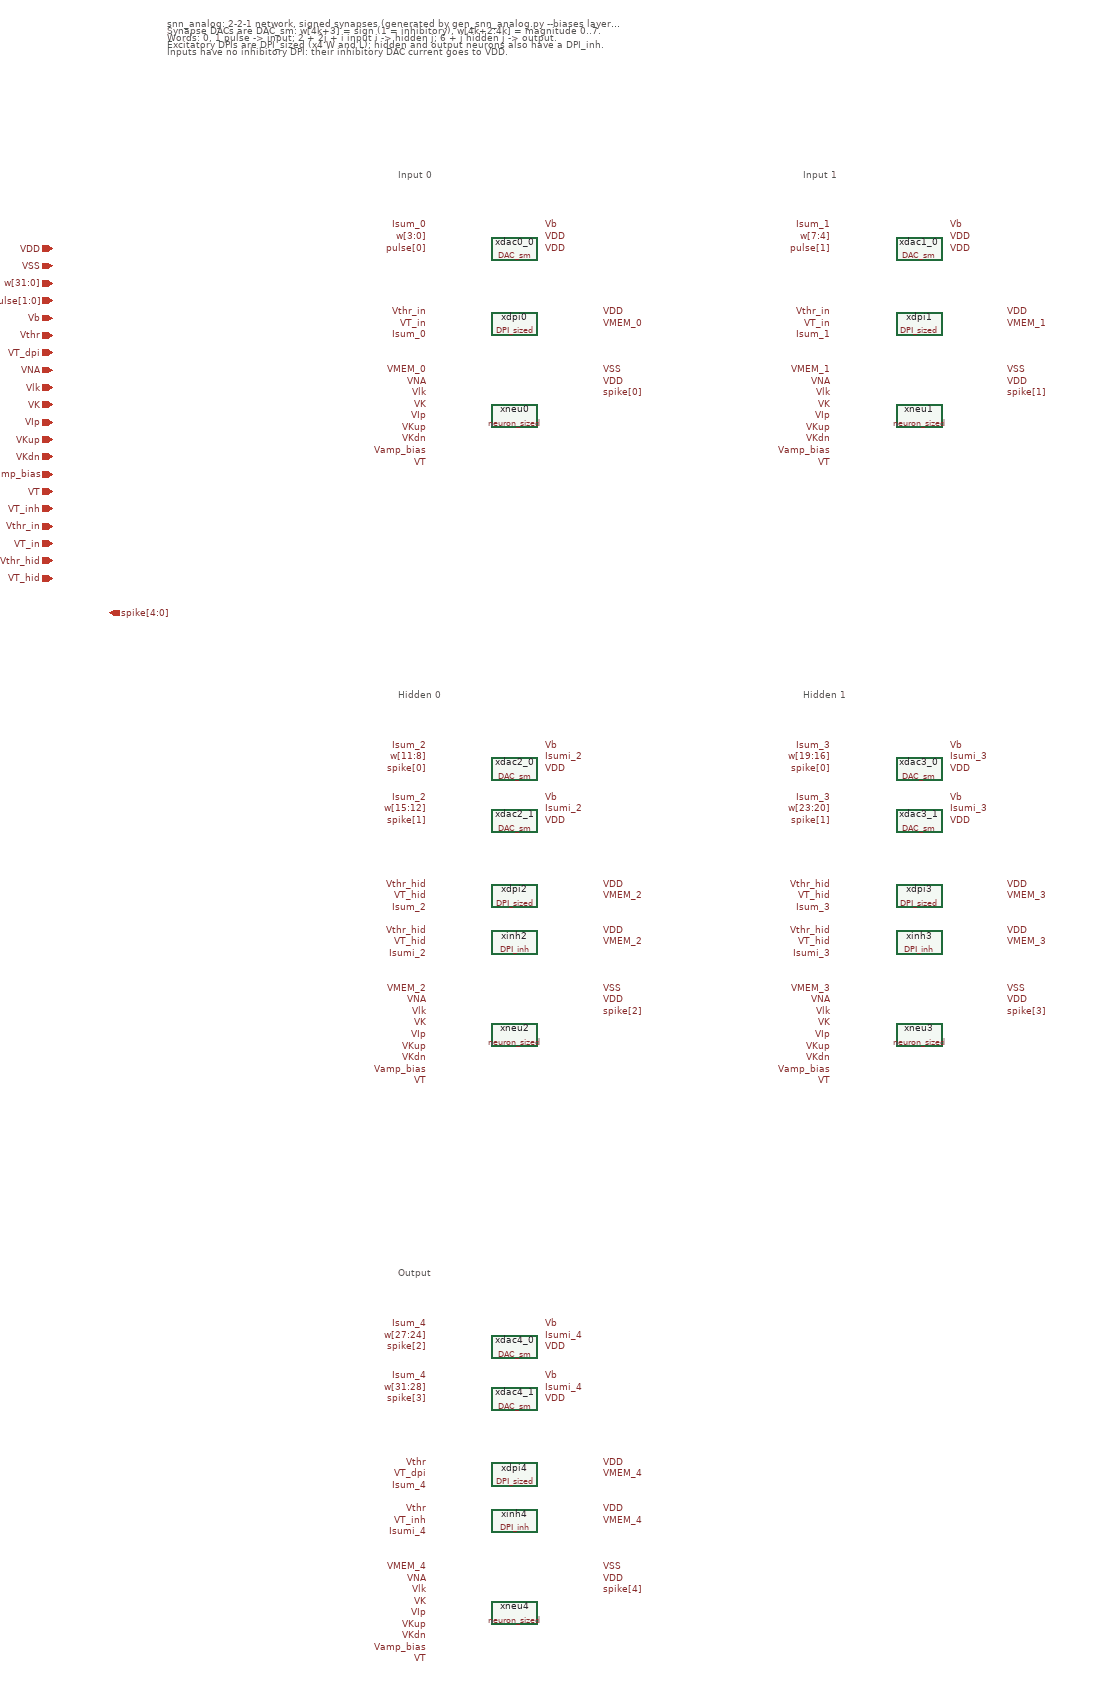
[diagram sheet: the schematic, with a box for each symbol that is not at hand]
v {xschem version=3.4.8RC file_version=1.3}
G {}
K {}
V {}
S {}
F {}
E {}
T {snn_analog: 2-2-1 network, signed synapses (generated by gen_snn_analog.py --biases layer).
Synapse DACs are DAC_sm: w[4k+3] = sign (1 = inhibitory), w[4k+2:4k] = magnitude 0..7.
Words: 0, 1 pulse -> input; 2 + 2j + i input i -> hidden j; 6 + j hidden j -> output.
Excitatory DPIs are DPI_sized (x4 W and L); hidden and output neurons also have a DPI_inh.
Inputs have no inhibitory DPI: their inhibitory DAC current goes to VDD.} -200 -1700 0 0 0.3 0.3 {}
T {Input 0} 200 -1440 0 0 0.4 0.4 {}
C {DAC_sm.sym} 400 -1300 0 0 {name=xdac0_0}
C {lab_pin.sym} 250 -1340 0 0 {name=l1 sig_type=std_logic lab=Isum_0}
C {lab_pin.sym} 250 -1320 0 0 {name=l2 sig_type=std_logic lab=w[3:0]}
C {lab_pin.sym} 250 -1300 0 0 {name=l3 sig_type=std_logic lab=pulse[0]}
C {lab_pin.sym} 450 -1340 0 1 {name=l4 sig_type=std_logic lab=Vb}
C {lab_pin.sym} 450 -1320 0 1 {name=l5 sig_type=std_logic lab=VDD}
C {lab_pin.sym} 450 -1300 0 1 {name=l6 sig_type=std_logic lab=VDD}
C {DPI_sized.sym} 400 -1170 0 0 {name=xdpi0}
C {lab_pin.sym} 550 -1190 0 1 {name=l7 sig_type=std_logic lab=VDD}
C {lab_pin.sym} 250 -1190 0 0 {name=l8 sig_type=std_logic lab=Vthr_in}
C {lab_pin.sym} 550 -1170 0 1 {name=l9 sig_type=std_logic lab=VMEM_0}
C {lab_pin.sym} 250 -1150 0 0 {name=l10 sig_type=std_logic lab=Isum_0}
C {lab_pin.sym} 250 -1170 0 0 {name=l11 sig_type=std_logic lab=VT_in}
C {neuron_sized.sym} 400 -1010 0 0 {name=xneu0}
C {lab_pin.sym} 550 -1090 0 1 {name=l12 sig_type=std_logic lab=VSS}
C {lab_pin.sym} 550 -1070 0 1 {name=l13 sig_type=std_logic lab=VDD}
C {lab_pin.sym} 250 -1090 0 0 {name=l14 sig_type=std_logic lab=VMEM_0}
C {lab_pin.sym} 550 -1050 0 1 {name=l15 sig_type=std_logic lab=spike[0]}
C {lab_pin.sym} 250 -1070 0 0 {name=l16 sig_type=std_logic lab=VNA}
C {lab_pin.sym} 250 -1050 0 0 {name=l17 sig_type=std_logic lab=Vlk}
C {lab_pin.sym} 250 -1030 0 0 {name=l18 sig_type=std_logic lab=VK}
C {lab_pin.sym} 250 -1010 0 0 {name=l19 sig_type=std_logic lab=VIp}
C {lab_pin.sym} 250 -990 0 0 {name=l20 sig_type=std_logic lab=VKup}
C {lab_pin.sym} 250 -970 0 0 {name=l21 sig_type=std_logic lab=VKdn}
C {lab_pin.sym} 250 -950 0 0 {name=l22 sig_type=std_logic lab=Vamp_bias}
C {lab_pin.sym} 250 -930 0 0 {name=l23 sig_type=std_logic lab=VT}
T {Input 1} 900 -1440 0 0 0.4 0.4 {}
C {DAC_sm.sym} 1100 -1300 0 0 {name=xdac1_0}
C {lab_pin.sym} 950 -1340 0 0 {name=l24 sig_type=std_logic lab=Isum_1}
C {lab_pin.sym} 950 -1320 0 0 {name=l25 sig_type=std_logic lab=w[7:4]}
C {lab_pin.sym} 950 -1300 0 0 {name=l26 sig_type=std_logic lab=pulse[1]}
C {lab_pin.sym} 1150 -1340 0 1 {name=l27 sig_type=std_logic lab=Vb}
C {lab_pin.sym} 1150 -1320 0 1 {name=l28 sig_type=std_logic lab=VDD}
C {lab_pin.sym} 1150 -1300 0 1 {name=l29 sig_type=std_logic lab=VDD}
C {DPI_sized.sym} 1100 -1170 0 0 {name=xdpi1}
C {lab_pin.sym} 1250 -1190 0 1 {name=l30 sig_type=std_logic lab=VDD}
C {lab_pin.sym} 950 -1190 0 0 {name=l31 sig_type=std_logic lab=Vthr_in}
C {lab_pin.sym} 1250 -1170 0 1 {name=l32 sig_type=std_logic lab=VMEM_1}
C {lab_pin.sym} 950 -1150 0 0 {name=l33 sig_type=std_logic lab=Isum_1}
C {lab_pin.sym} 950 -1170 0 0 {name=l34 sig_type=std_logic lab=VT_in}
C {neuron_sized.sym} 1100 -1010 0 0 {name=xneu1}
C {lab_pin.sym} 1250 -1090 0 1 {name=l35 sig_type=std_logic lab=VSS}
C {lab_pin.sym} 1250 -1070 0 1 {name=l36 sig_type=std_logic lab=VDD}
C {lab_pin.sym} 950 -1090 0 0 {name=l37 sig_type=std_logic lab=VMEM_1}
C {lab_pin.sym} 1250 -1050 0 1 {name=l38 sig_type=std_logic lab=spike[1]}
C {lab_pin.sym} 950 -1070 0 0 {name=l39 sig_type=std_logic lab=VNA}
C {lab_pin.sym} 950 -1050 0 0 {name=l40 sig_type=std_logic lab=Vlk}
C {lab_pin.sym} 950 -1030 0 0 {name=l41 sig_type=std_logic lab=VK}
C {lab_pin.sym} 950 -1010 0 0 {name=l42 sig_type=std_logic lab=VIp}
C {lab_pin.sym} 950 -990 0 0 {name=l43 sig_type=std_logic lab=VKup}
C {lab_pin.sym} 950 -970 0 0 {name=l44 sig_type=std_logic lab=VKdn}
C {lab_pin.sym} 950 -950 0 0 {name=l45 sig_type=std_logic lab=Vamp_bias}
C {lab_pin.sym} 950 -930 0 0 {name=l46 sig_type=std_logic lab=VT}
T {Hidden 0} 200 -540 0 0 0.4 0.4 {}
C {DAC_sm.sym} 400 -400 0 0 {name=xdac2_0}
C {lab_pin.sym} 250 -440 0 0 {name=l47 sig_type=std_logic lab=Isum_2}
C {lab_pin.sym} 250 -420 0 0 {name=l48 sig_type=std_logic lab=w[11:8]}
C {lab_pin.sym} 250 -400 0 0 {name=l49 sig_type=std_logic lab=spike[0]}
C {lab_pin.sym} 450 -440 0 1 {name=l50 sig_type=std_logic lab=Vb}
C {lab_pin.sym} 450 -420 0 1 {name=l51 sig_type=std_logic lab=Isumi_2}
C {lab_pin.sym} 450 -400 0 1 {name=l52 sig_type=std_logic lab=VDD}
C {DAC_sm.sym} 400 -310 0 0 {name=xdac2_1}
C {lab_pin.sym} 250 -350 0 0 {name=l53 sig_type=std_logic lab=Isum_2}
C {lab_pin.sym} 250 -330 0 0 {name=l54 sig_type=std_logic lab=w[15:12]}
C {lab_pin.sym} 250 -310 0 0 {name=l55 sig_type=std_logic lab=spike[1]}
C {lab_pin.sym} 450 -350 0 1 {name=l56 sig_type=std_logic lab=Vb}
C {lab_pin.sym} 450 -330 0 1 {name=l57 sig_type=std_logic lab=Isumi_2}
C {lab_pin.sym} 450 -310 0 1 {name=l58 sig_type=std_logic lab=VDD}
C {DPI_sized.sym} 400 -180 0 0 {name=xdpi2}
C {lab_pin.sym} 550 -200 0 1 {name=l59 sig_type=std_logic lab=VDD}
C {lab_pin.sym} 250 -200 0 0 {name=l60 sig_type=std_logic lab=Vthr_hid}
C {lab_pin.sym} 550 -180 0 1 {name=l61 sig_type=std_logic lab=VMEM_2}
C {lab_pin.sym} 250 -160 0 0 {name=l62 sig_type=std_logic lab=Isum_2}
C {lab_pin.sym} 250 -180 0 0 {name=l63 sig_type=std_logic lab=VT_hid}
C {DPI_inh.sym} 400 -100 0 0 {name=xinh2}
C {lab_pin.sym} 250 -120 0 0 {name=l64 sig_type=std_logic lab=Vthr_hid}
C {lab_pin.sym} 250 -100 0 0 {name=l65 sig_type=std_logic lab=VT_hid}
C {lab_pin.sym} 250 -80 0 0 {name=l66 sig_type=std_logic lab=Isumi_2}
C {lab_pin.sym} 550 -120 0 1 {name=l67 sig_type=std_logic lab=VDD}
C {lab_pin.sym} 550 -100 0 1 {name=l68 sig_type=std_logic lab=VMEM_2}
C {neuron_sized.sym} 400 60 0 0 {name=xneu2}
C {lab_pin.sym} 550 -20 0 1 {name=l69 sig_type=std_logic lab=VSS}
C {lab_pin.sym} 550 0 0 1 {name=l70 sig_type=std_logic lab=VDD}
C {lab_pin.sym} 250 -20 0 0 {name=l71 sig_type=std_logic lab=VMEM_2}
C {lab_pin.sym} 550 20 0 1 {name=l72 sig_type=std_logic lab=spike[2]}
C {lab_pin.sym} 250 0 0 0 {name=l73 sig_type=std_logic lab=VNA}
C {lab_pin.sym} 250 20 0 0 {name=l74 sig_type=std_logic lab=Vlk}
C {lab_pin.sym} 250 40 0 0 {name=l75 sig_type=std_logic lab=VK}
C {lab_pin.sym} 250 60 0 0 {name=l76 sig_type=std_logic lab=VIp}
C {lab_pin.sym} 250 80 0 0 {name=l77 sig_type=std_logic lab=VKup}
C {lab_pin.sym} 250 100 0 0 {name=l78 sig_type=std_logic lab=VKdn}
C {lab_pin.sym} 250 120 0 0 {name=l79 sig_type=std_logic lab=Vamp_bias}
C {lab_pin.sym} 250 140 0 0 {name=l80 sig_type=std_logic lab=VT}
T {Hidden 1} 900 -540 0 0 0.4 0.4 {}
C {DAC_sm.sym} 1100 -400 0 0 {name=xdac3_0}
C {lab_pin.sym} 950 -440 0 0 {name=l81 sig_type=std_logic lab=Isum_3}
C {lab_pin.sym} 950 -420 0 0 {name=l82 sig_type=std_logic lab=w[19:16]}
C {lab_pin.sym} 950 -400 0 0 {name=l83 sig_type=std_logic lab=spike[0]}
C {lab_pin.sym} 1150 -440 0 1 {name=l84 sig_type=std_logic lab=Vb}
C {lab_pin.sym} 1150 -420 0 1 {name=l85 sig_type=std_logic lab=Isumi_3}
C {lab_pin.sym} 1150 -400 0 1 {name=l86 sig_type=std_logic lab=VDD}
C {DAC_sm.sym} 1100 -310 0 0 {name=xdac3_1}
C {lab_pin.sym} 950 -350 0 0 {name=l87 sig_type=std_logic lab=Isum_3}
C {lab_pin.sym} 950 -330 0 0 {name=l88 sig_type=std_logic lab=w[23:20]}
C {lab_pin.sym} 950 -310 0 0 {name=l89 sig_type=std_logic lab=spike[1]}
C {lab_pin.sym} 1150 -350 0 1 {name=l90 sig_type=std_logic lab=Vb}
C {lab_pin.sym} 1150 -330 0 1 {name=l91 sig_type=std_logic lab=Isumi_3}
C {lab_pin.sym} 1150 -310 0 1 {name=l92 sig_type=std_logic lab=VDD}
C {DPI_sized.sym} 1100 -180 0 0 {name=xdpi3}
C {lab_pin.sym} 1250 -200 0 1 {name=l93 sig_type=std_logic lab=VDD}
C {lab_pin.sym} 950 -200 0 0 {name=l94 sig_type=std_logic lab=Vthr_hid}
C {lab_pin.sym} 1250 -180 0 1 {name=l95 sig_type=std_logic lab=VMEM_3}
C {lab_pin.sym} 950 -160 0 0 {name=l96 sig_type=std_logic lab=Isum_3}
C {lab_pin.sym} 950 -180 0 0 {name=l97 sig_type=std_logic lab=VT_hid}
C {DPI_inh.sym} 1100 -100 0 0 {name=xinh3}
C {lab_pin.sym} 950 -120 0 0 {name=l98 sig_type=std_logic lab=Vthr_hid}
C {lab_pin.sym} 950 -100 0 0 {name=l99 sig_type=std_logic lab=VT_hid}
C {lab_pin.sym} 950 -80 0 0 {name=l100 sig_type=std_logic lab=Isumi_3}
C {lab_pin.sym} 1250 -120 0 1 {name=l101 sig_type=std_logic lab=VDD}
C {lab_pin.sym} 1250 -100 0 1 {name=l102 sig_type=std_logic lab=VMEM_3}
C {neuron_sized.sym} 1100 60 0 0 {name=xneu3}
C {lab_pin.sym} 1250 -20 0 1 {name=l103 sig_type=std_logic lab=VSS}
C {lab_pin.sym} 1250 0 0 1 {name=l104 sig_type=std_logic lab=VDD}
C {lab_pin.sym} 950 -20 0 0 {name=l105 sig_type=std_logic lab=VMEM_3}
C {lab_pin.sym} 1250 20 0 1 {name=l106 sig_type=std_logic lab=spike[3]}
C {lab_pin.sym} 950 0 0 0 {name=l107 sig_type=std_logic lab=VNA}
C {lab_pin.sym} 950 20 0 0 {name=l108 sig_type=std_logic lab=Vlk}
C {lab_pin.sym} 950 40 0 0 {name=l109 sig_type=std_logic lab=VK}
C {lab_pin.sym} 950 60 0 0 {name=l110 sig_type=std_logic lab=VIp}
C {lab_pin.sym} 950 80 0 0 {name=l111 sig_type=std_logic lab=VKup}
C {lab_pin.sym} 950 100 0 0 {name=l112 sig_type=std_logic lab=VKdn}
C {lab_pin.sym} 950 120 0 0 {name=l113 sig_type=std_logic lab=Vamp_bias}
C {lab_pin.sym} 950 140 0 0 {name=l114 sig_type=std_logic lab=VT}
T {Output} 200 460 0 0 0.4 0.4 {}
C {DAC_sm.sym} 400 600 0 0 {name=xdac4_0}
C {lab_pin.sym} 250 560 0 0 {name=l115 sig_type=std_logic lab=Isum_4}
C {lab_pin.sym} 250 580 0 0 {name=l116 sig_type=std_logic lab=w[27:24]}
C {lab_pin.sym} 250 600 0 0 {name=l117 sig_type=std_logic lab=spike[2]}
C {lab_pin.sym} 450 560 0 1 {name=l118 sig_type=std_logic lab=Vb}
C {lab_pin.sym} 450 580 0 1 {name=l119 sig_type=std_logic lab=Isumi_4}
C {lab_pin.sym} 450 600 0 1 {name=l120 sig_type=std_logic lab=VDD}
C {DAC_sm.sym} 400 690 0 0 {name=xdac4_1}
C {lab_pin.sym} 250 650 0 0 {name=l121 sig_type=std_logic lab=Isum_4}
C {lab_pin.sym} 250 670 0 0 {name=l122 sig_type=std_logic lab=w[31:28]}
C {lab_pin.sym} 250 690 0 0 {name=l123 sig_type=std_logic lab=spike[3]}
C {lab_pin.sym} 450 650 0 1 {name=l124 sig_type=std_logic lab=Vb}
C {lab_pin.sym} 450 670 0 1 {name=l125 sig_type=std_logic lab=Isumi_4}
C {lab_pin.sym} 450 690 0 1 {name=l126 sig_type=std_logic lab=VDD}
C {DPI_sized.sym} 400 820 0 0 {name=xdpi4}
C {lab_pin.sym} 550 800 0 1 {name=l127 sig_type=std_logic lab=VDD}
C {lab_pin.sym} 250 800 0 0 {name=l128 sig_type=std_logic lab=Vthr}
C {lab_pin.sym} 550 820 0 1 {name=l129 sig_type=std_logic lab=VMEM_4}
C {lab_pin.sym} 250 840 0 0 {name=l130 sig_type=std_logic lab=Isum_4}
C {lab_pin.sym} 250 820 0 0 {name=l131 sig_type=std_logic lab=VT_dpi}
C {DPI_inh.sym} 400 900 0 0 {name=xinh4}
C {lab_pin.sym} 250 880 0 0 {name=l132 sig_type=std_logic lab=Vthr}
C {lab_pin.sym} 250 900 0 0 {name=l133 sig_type=std_logic lab=VT_inh}
C {lab_pin.sym} 250 920 0 0 {name=l134 sig_type=std_logic lab=Isumi_4}
C {lab_pin.sym} 550 880 0 1 {name=l135 sig_type=std_logic lab=VDD}
C {lab_pin.sym} 550 900 0 1 {name=l136 sig_type=std_logic lab=VMEM_4}
C {neuron_sized.sym} 400 1060 0 0 {name=xneu4}
C {lab_pin.sym} 550 980 0 1 {name=l137 sig_type=std_logic lab=VSS}
C {lab_pin.sym} 550 1000 0 1 {name=l138 sig_type=std_logic lab=VDD}
C {lab_pin.sym} 250 980 0 0 {name=l139 sig_type=std_logic lab=VMEM_4}
C {lab_pin.sym} 550 1020 0 1 {name=l140 sig_type=std_logic lab=spike[4]}
C {lab_pin.sym} 250 1000 0 0 {name=l141 sig_type=std_logic lab=VNA}
C {lab_pin.sym} 250 1020 0 0 {name=l142 sig_type=std_logic lab=Vlk}
C {lab_pin.sym} 250 1040 0 0 {name=l143 sig_type=std_logic lab=VK}
C {lab_pin.sym} 250 1060 0 0 {name=l144 sig_type=std_logic lab=VIp}
C {lab_pin.sym} 250 1080 0 0 {name=l145 sig_type=std_logic lab=VKup}
C {lab_pin.sym} 250 1100 0 0 {name=l146 sig_type=std_logic lab=VKdn}
C {lab_pin.sym} 250 1120 0 0 {name=l147 sig_type=std_logic lab=Vamp_bias}
C {lab_pin.sym} 250 1140 0 0 {name=l148 sig_type=std_logic lab=VT}
C {iopin.sym} -400 -1300 0 0 {name=p0 lab=VDD}
C {iopin.sym} -400 -1270 0 0 {name=p1 lab=VSS}
C {ipin.sym} -400 -1240 0 0 {name=p2 lab=w[31:0]}
C {ipin.sym} -400 -1210 0 0 {name=p3 lab=pulse[1:0]}
C {ipin.sym} -400 -1180 0 0 {name=p4 lab=Vb}
C {ipin.sym} -400 -1150 0 0 {name=p5 lab=Vthr}
C {ipin.sym} -400 -1120 0 0 {name=p6 lab=VT_dpi}
C {ipin.sym} -400 -1090 0 0 {name=p7 lab=VNA}
C {ipin.sym} -400 -1060 0 0 {name=p8 lab=Vlk}
C {ipin.sym} -400 -1030 0 0 {name=p9 lab=VK}
C {ipin.sym} -400 -1000 0 0 {name=p10 lab=VIp}
C {ipin.sym} -400 -970 0 0 {name=p11 lab=VKup}
C {ipin.sym} -400 -940 0 0 {name=p12 lab=VKdn}
C {ipin.sym} -400 -910 0 0 {name=p13 lab=Vamp_bias}
C {ipin.sym} -400 -880 0 0 {name=p14 lab=VT}
C {ipin.sym} -400 -850 0 0 {name=p15 lab=VT_inh}
C {ipin.sym} -400 -820 0 0 {name=p16 lab=Vthr_in}
C {ipin.sym} -400 -790 0 0 {name=p17 lab=VT_in}
C {ipin.sym} -400 -760 0 0 {name=p18 lab=Vthr_hid}
C {ipin.sym} -400 -730 0 0 {name=p19 lab=VT_hid}
C {opin.sym} -300 -670 0 0 {name=p20 lab=spike[4:0]}
